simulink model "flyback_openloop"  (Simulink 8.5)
settings: Solver=ode45  StartTime=0.0  StopTime=0.006  RelTol=1e-3

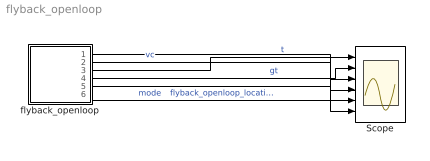
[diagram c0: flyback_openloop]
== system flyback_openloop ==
  Scope : Scope  NumInputPorts=6
  flyback_openloop : Stateflow chart  TreatAsAtomicUnit=on
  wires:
  flyback_openloop/3(t_out) -> Scope/1  "t"
  flyback_openloop/4(gt_out) -> Scope/2  "gt"
  flyback_openloop/2(vc_out) -> Scope/3  "vc"
  flyback_openloop/1(il_out) -> Scope/4  "il"
  flyback_openloop/6(flyback_openloop_location) -> Scope/5  "flyback_openloop_location"
  flyback_openloop/5(mode_out) -> Scope/6  "mode"

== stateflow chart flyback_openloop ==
  state charging
    du:
    il_dot = b1c * Vin;
    vc_dot = a22c * vc;
    t_dot = 1;
    gt_dot = 1;
    mode_dot = 0;
    il_out=il;
    vc_out=vc;
    t_out=t;
    gt_out=gt;
    mode_out=mode;
    flyback_openloop_location =1;
  state discharging
    du:
    il_dot = a12o * vc;
    vc_dot = a21o * il + a22o * vc;
    t_dot = 1;
    gt_dot = 1;
    mode_dot = 0;
    il_out=il;
    vc_out=vc;
    t_out=t;
    gt_out=gt;
    mode_out=mode;
    flyback_openloop_location =2;
  charging -> discharging : [t >= D * T] {t = 0; gt = gt; vc = vc; il = il; mode = 2;}
  (default) -> charging : {il = 0; vc = 0; t = 0; gt = 0; mode = 1;}
  discharging -> charging : [t >= (1 - D) * T] {t = 0; gt = gt; vc = vc; il = il; mode = 1;}
